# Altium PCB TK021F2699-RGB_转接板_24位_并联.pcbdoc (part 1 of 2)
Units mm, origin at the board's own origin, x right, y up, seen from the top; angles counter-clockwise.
Board outline 79.4 x 75.01 mm, 2 copper layers (Top Layer, Bottom Layer); 9 components, 37 nets, 108 pads, 115 vias.

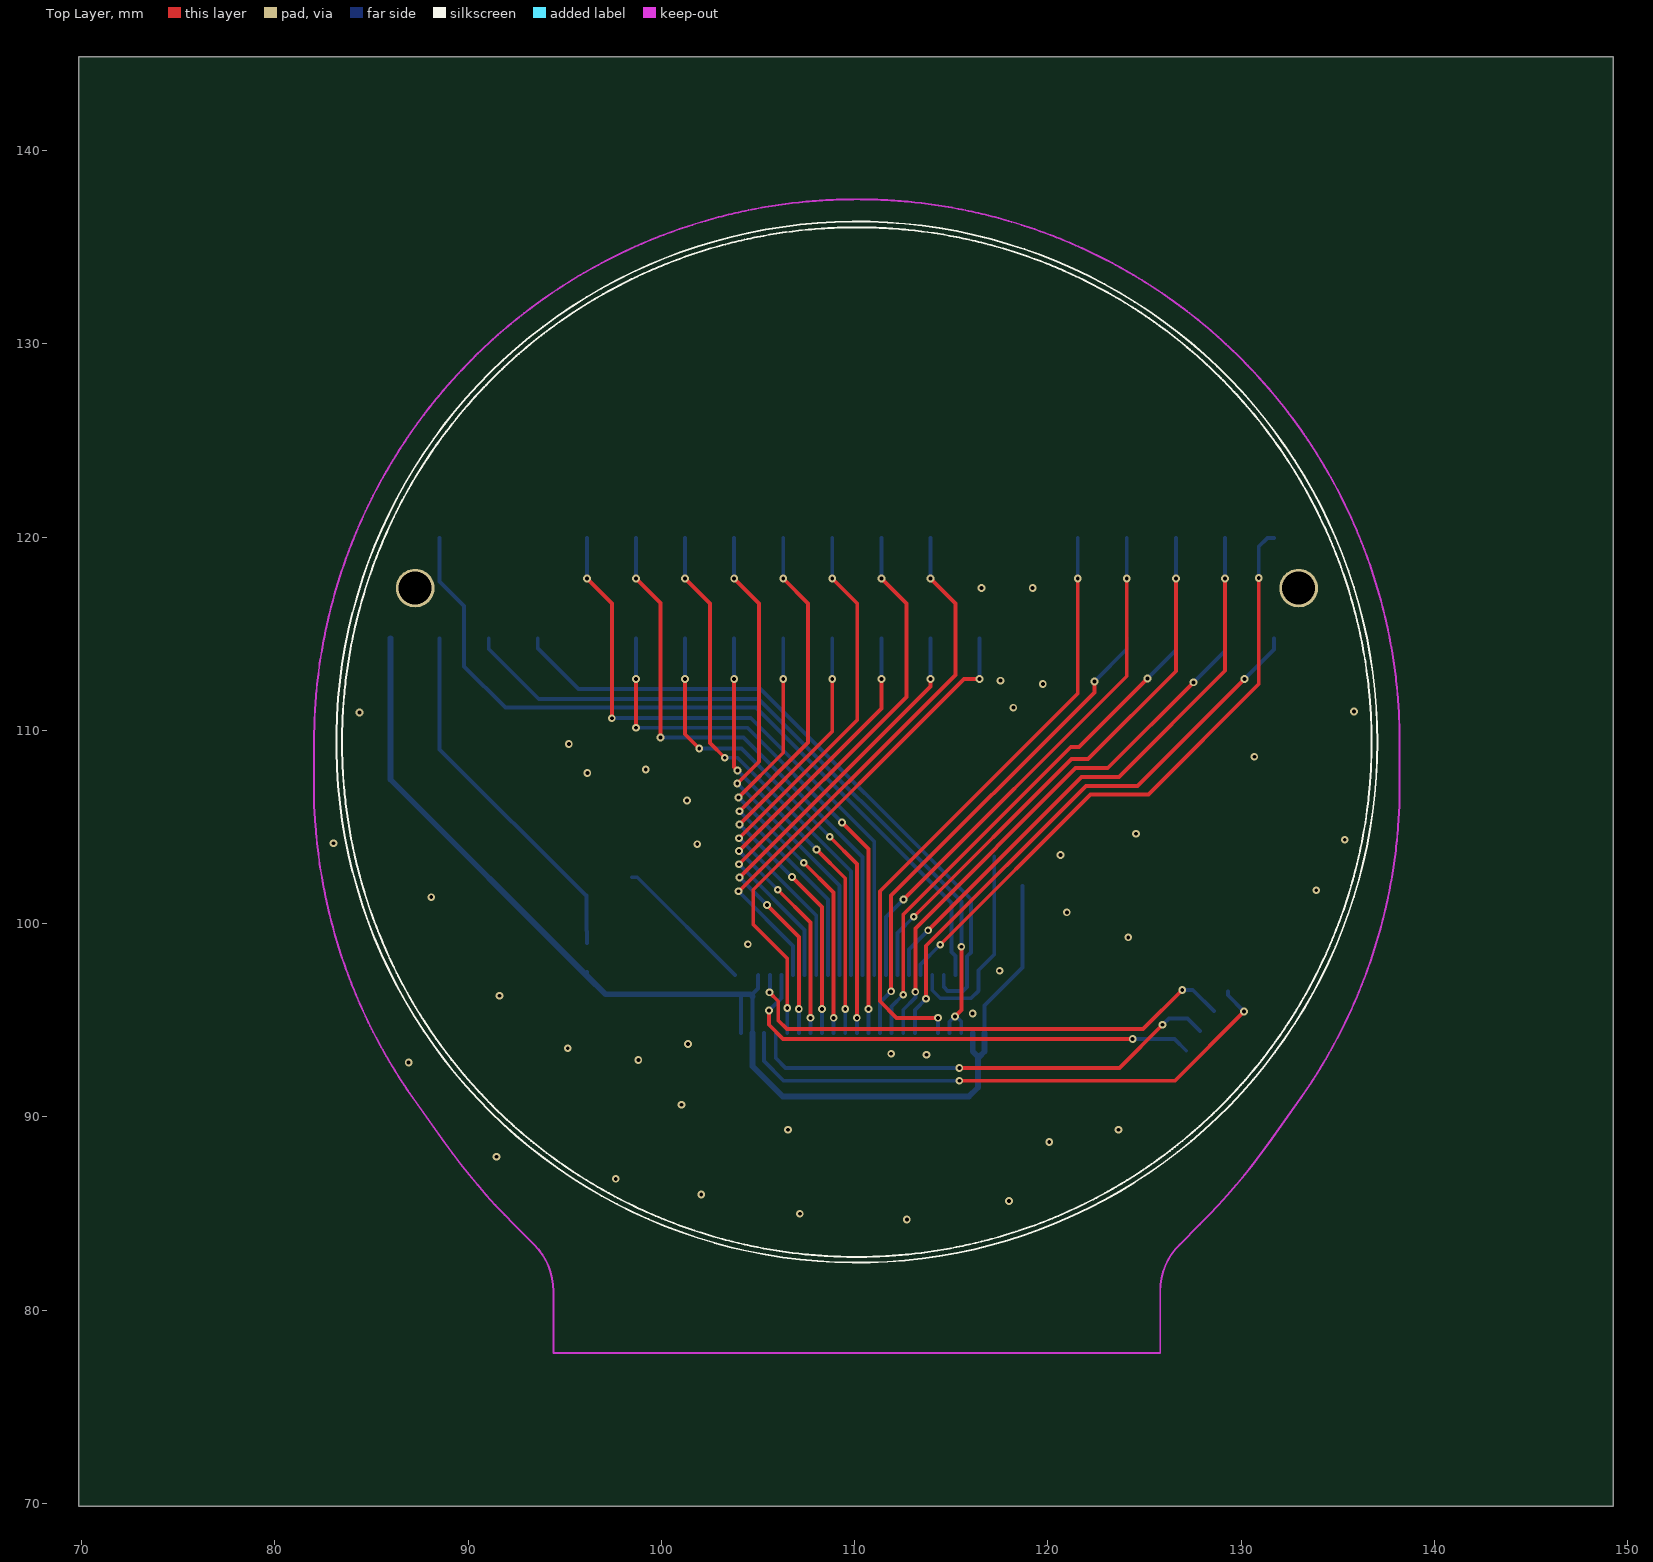
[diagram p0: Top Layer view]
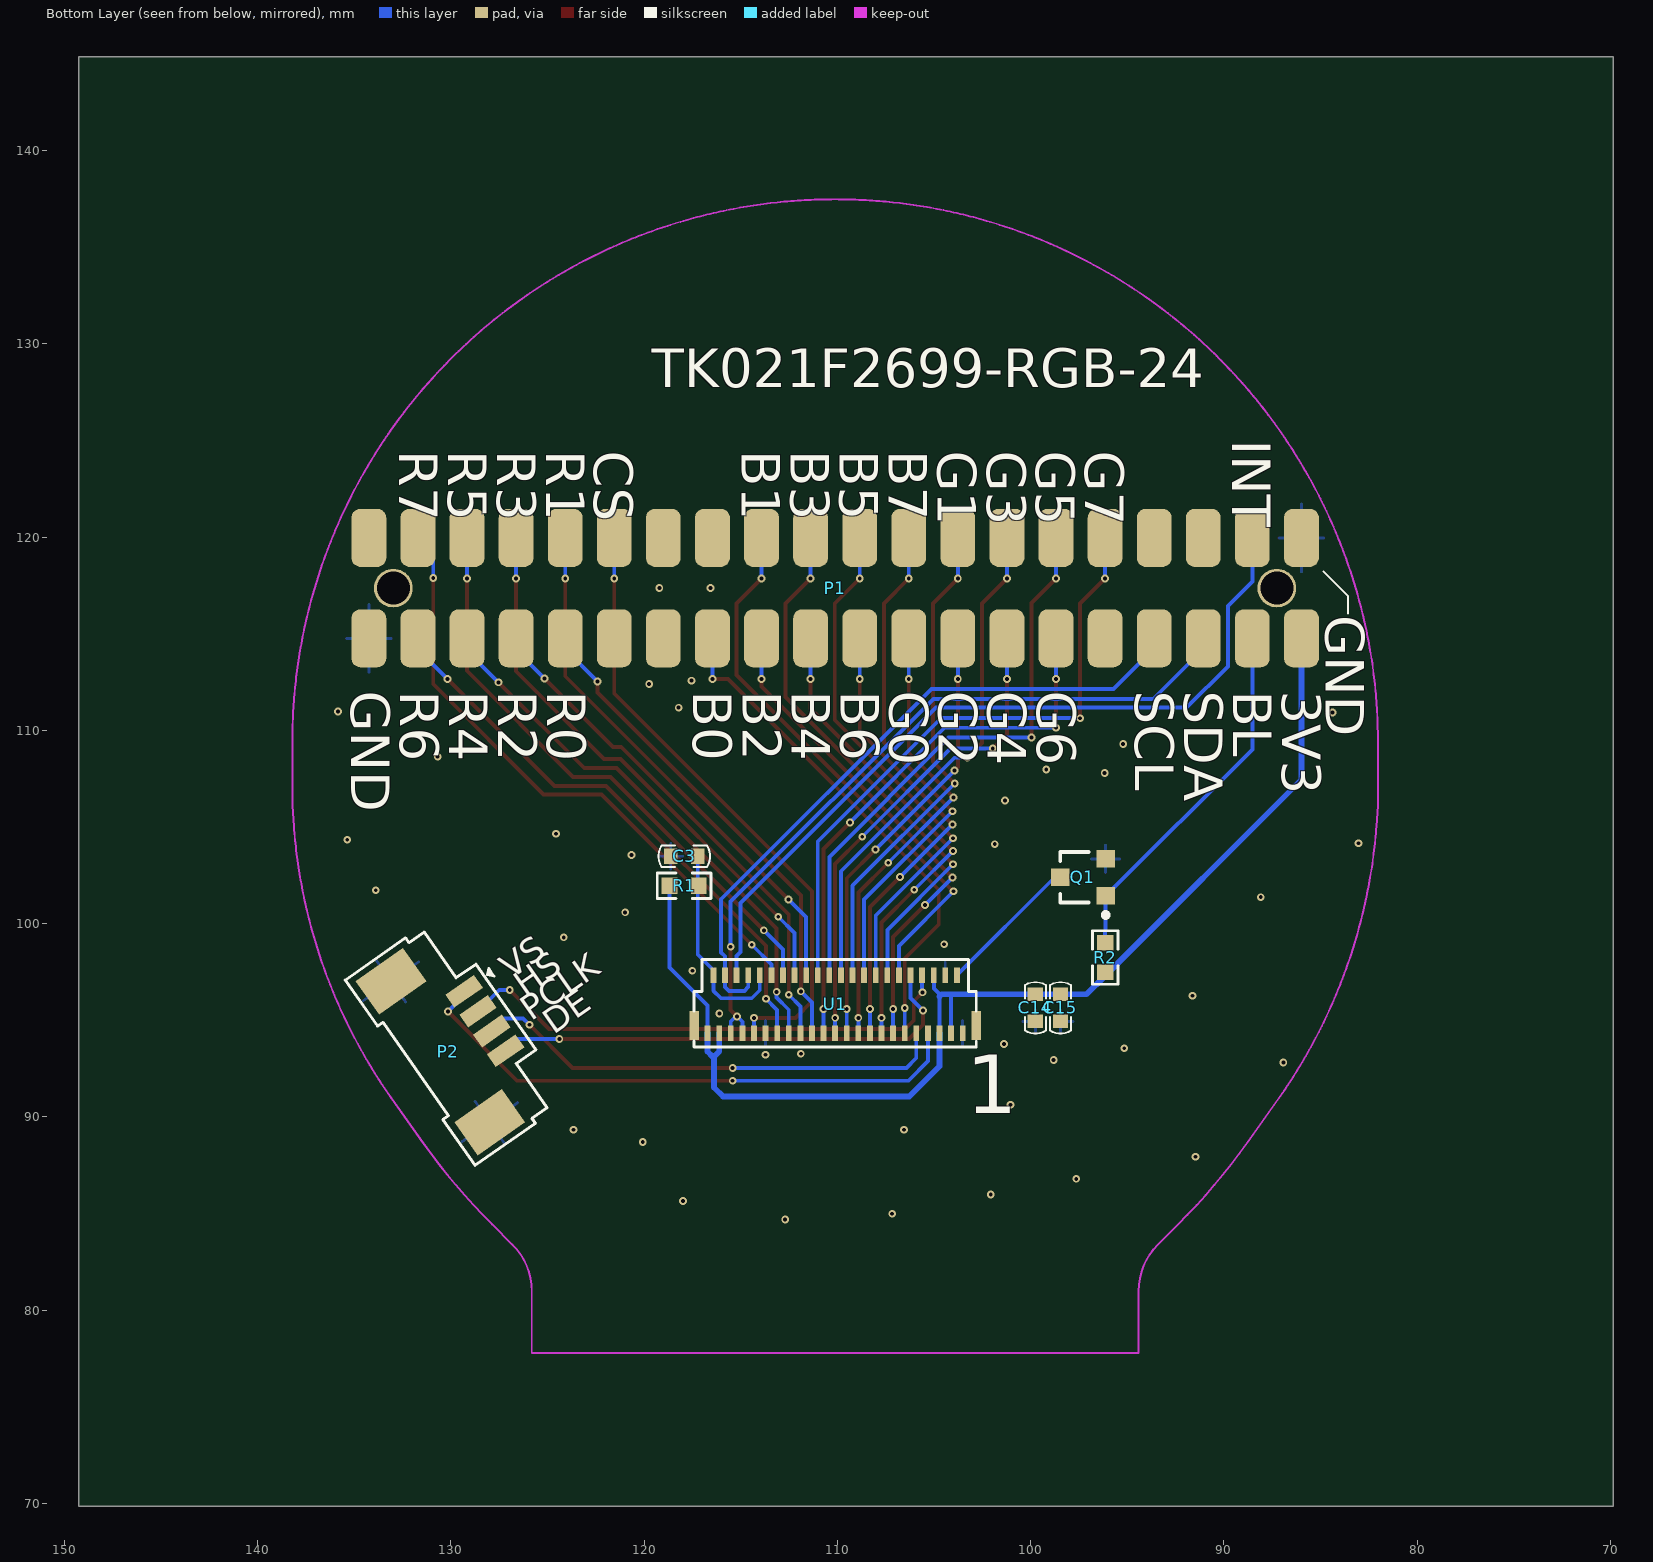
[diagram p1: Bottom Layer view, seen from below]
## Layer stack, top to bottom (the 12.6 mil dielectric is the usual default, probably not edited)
Top Layer: signal copper (thickness not stored)
Dielectric: dielectric 0.32, FR-4, Dk 4.8
Bottom Layer: signal copper (thickness not stored)

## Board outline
149.25,69.85 69.85,69.85 69.85,144.856 149.25,144.856

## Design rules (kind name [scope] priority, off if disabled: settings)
Clearance [All] p1: gap=0.178 ignorepadtopadclearanceinfootprint=FALSE except(0: Track-Poly SMDPad-Poly THPad-Poly Via-Poly Fill-Poly Region-Poly Poly-Poly Poly-Hole; 0.15: Track-Track Track-SMDPad SMDPad-SMDPad Track-THPad SMDPad-THPad THPad-THPad Track-Via SMDPad-Via THPad-Via Via-Via Track-Fill SMDPad-Fill THPad-Fill Via-Fill Fill-Fill Track-Region SMDPad-Region THPad-Region Via-Region Fill-Region Region-Region Track-Text SMDPad-Text THPad-Text Via-Text Fill-Text Region-Text Poly-Text Text-Text Track-Sheet SMDPad-Sheet THPad-Sheet Via-Sheet Fill-Sheet Region-Sheet Poly-Sheet Text-Sheet Track-Hole SMDPad-Hole THPad-Hole Via-Hole Fill-Hole Region-Hole Text-Hole Sheet-Hole)
Clearance Clearance_Polygon [All] p1: gap=0.178 ignorepadtopadclearanceinfootprint=FALSE except(0: Track-Text SMDPad-Text THPad-Text Via-Text Fill-Text Region-Text Poly-Text Text-Text Text-Hole; 0.15: Track-Track Track-SMDPad SMDPad-SMDPad Track-THPad SMDPad-THPad THPad-THPad Track-Via SMDPad-Via THPad-Via Via-Via Track-Fill SMDPad-Fill THPad-Fill Via-Fill Fill-Fill Track-Poly SMDPad-Poly THPad-Poly Via-Poly Fill-Poly Region-Poly Poly-Poly Track-Sheet SMDPad-Sheet THPad-Sheet Via-Sheet Fill-Sheet Region-Sheet Poly-Sheet Text-Sheet Track-Hole SMDPad-Hole THPad-Hole Via-Hole Fill-Hole Poly-Hole Sheet-Hole; 0.18: Track-Region SMDPad-Region THPad-Region Via-Region Fill-Region Region-Region Region-Hole)
DiffPairsRouting [All] p1: maxuncoupledlength=500 minlimit=5.9055 maxlimit=10 mostfreqgap=7.874 toplayer_minwidth=7.874 toplayer_prefwidth=7.874 toplayer_maxwidth=7.874 bottomlayer_minwidth=7.874 bottomlayer_prefwidth=7.874 bottomlayer_maxwidth=7.874
PasteMaskExpansion [All] p1:
PolygonConnect [All] p1: connectstyle=Relief reliefentries=4 reliefconductorwidth=5.9055 polygonreliefangle="90 Angle" airgapwidth=10
PolygonConnect PolygonConnect_1 [All] p1: connectstyle=Direct reliefentries=4 reliefconductorwidth=10 polygonreliefangle="90 Angle" airgapwidth=10
RoutingVias [All] p1: viastyle="Through Hole" holewidth=7.874 minholewidth=7.874 maxholewidth=27.9922 width=15.748 minwidth=15.748 maxwidth=50
SolderMaskExpansion [All] p1: useseparateexpansions=TRUE expansion=3.937 expansionbottom=3.937
Width [All] p1: maxlimit=16 minlimit=8 preferedwidth=8
1 further rules are at their usual default settings.

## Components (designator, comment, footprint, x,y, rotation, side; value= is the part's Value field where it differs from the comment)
C3 "CC0603KRX7R9BB104" C0603 117.932,103.48 r0 bottom
C14 "104" C0603-1 99.746,96.345 r270 bottom
C15 "475" C0603-2 98.45,96.345 r270 bottom
P1 "PIN_Header_40PIN" P_Head_2x20 134.242,119.964 r180 bottom locked
P2 "BHEADSMD1x4" BHEADSMD1x4 129.311,96.495 r55 bottom
Q1 "SI2302" SOT23A 96.114,101.448 r90 bottom
R1 "0603WAF1802T5E" R0603 117.932,101.956 r0 bottom
R2 "0603WAF1802T5E" R0603 96.139,98.247 r270 bottom
U1 "TK-RGB-45P" tk043f-45p 103.512,94.336 r0 bottom locked

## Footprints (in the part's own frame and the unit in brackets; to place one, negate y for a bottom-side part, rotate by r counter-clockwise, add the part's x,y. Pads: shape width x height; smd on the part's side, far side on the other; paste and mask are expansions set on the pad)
BHEADSMD1x4 [mil]
  rect 32x71 smd: 1(0,0) 2(-49.21,0) 3(-98.43,0) 4(-147.64,0)
  rect 83x118 smd: 5(102.36,110.24) 6(-248.03,110.24)
  silkscreen extent -303,-68 158,185
C0603 [mm]
  rect 0.7x0.8 smd: 1(-0.712,-0.007) 2(0.688,-0.007)
  silkscreen extent -1.33,-0.56 1.31,0.54
C0603-1 [mm]
  rect 0.7x0.8 smd: 1(0,0) 2(1.4,0)
  silkscreen extent -0.62,-0.55 2.02,0.55
C0603-2 [mm]
  rect 0.7x0.8 smd: 1(0,0) 2(1.4,0)
  silkscreen extent -0.62,-0.55 2.02,0.55
P_Head_2x20 [mm]
  round 2 hole 1.7: 0(1.27,-2.6) 0(46.99,-2.6)
  rrect50% 1.8x3 smd: 1(0,0) 2(0,-5.2) 3(2.54,0) 4(2.54,-5.2) 5(5.08,0) 6(5.08,-5.2) 7(7.62,0) 8(7.62,-5.2) 9(10.16,0) 10(10.16,-5.2) 11(12.7,0) 12(12.7,-5.2) 13(15.24,0) 14(15.24,-5.2) 15(17.78,0) 16(17.78,-5.2) 17(20.32,0) 18(20.32,-5.2) 19(22.86,0) 20(22.86,-5.2) 21(25.4,0) 22(25.4,-5.2) 23(27.94,0) 24(27.94,-5.2) 25(30.48,0) 26(30.48,-5.2) 27(33.02,0) 28(33.02,-5.2) 29(35.56,0) 30(35.56,-5.2) 31(38.1,0) 32(38.1,-5.2) 33(40.64,0) 34(40.64,-5.2) 35(43.18,0) 36(43.18,-5.2) 37(45.72,0) 38(45.72,-5.2) 39(48.26,0) 40(48.26,-5.2)
R0603 [mm]
  rect 0.806x0.864 smd: 1(-0.753,0) 2(0.753,0)
  silkscreen extent -1.39,-0.66 1.39,0.66
SOT23A [mm]
  rect 0.9x0.95 smd: 1(0,0) 2(1.9,0) 3(0.95,2.35)
  silkscreen extent -1.12,-0.12 2.25,2.35
tk043f-45p [mm]
  rect 0.5x1.5 smd: 0(-0.7,-0.4) 0(13.9,-0.4)
  rect 0.3x0.8 smd: 1(0,0) 2(0.3,-3) 3(0.6,0) 4(0.9,-3) 5(1.2,0) 6(1.5,-3) 7(1.8,0) 8(2.1,-3) 9(2.4,0) 10(2.7,-3) 11(3,0) 12(3.3,-3) 13(3.6,0) 14(3.9,-3) 15(4.2,0) 16(4.5,-3) 17(4.8,0) 18(5.1,-3) 19(5.4,0) 20(5.7,-3) 21(6,0) 22(6.3,-3) 23(6.6,0) 24(6.9,-3) 25(7.2,0) 26(7.5,-3) 27(7.8,0) 28(8.1,-3) 29(8.4,0) 30(8.7,-3) 31(9,0) 32(9.3,-3) 33(9.6,0) 34(9.9,-3) 35(10.2,0) 36(10.5,-3) 37(10.8,0) 38(11.1,-3) 39(11.4,0) 40(11.7,-3) 41(12,0) 42(12.3,-3) 43(12.6,0) 44(12.9,-3) 45(13.2,0)
  silkscreen extent -0.7,-3.8 13.9,0.73

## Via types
v1: diameter 0.4, hole 0.2, Top Layer to Bottom Layer, 115 vias

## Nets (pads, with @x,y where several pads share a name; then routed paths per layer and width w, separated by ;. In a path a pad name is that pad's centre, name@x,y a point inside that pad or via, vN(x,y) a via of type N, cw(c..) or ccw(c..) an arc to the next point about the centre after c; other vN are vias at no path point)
3.3V: C14.1 C15.1 P1.40 R1.2 R2.2 U1.3 U1.5 U1.6 U1.43 U1.45 | length 62.9
  Bottom Layer w0.2: R2.2@96.139,97.307 R2.2@96.139,97.494 ; U1.3@104.112,94.336 104.112,96.33 104.127,96.345 ; U1.5@104.712,94.336 104.712,96.228 104.712,96.355 105.004,96.647 105.004,97.328 U1.6@105.012,97.336 ; U1.45@116.712,94.336 116.712,95.757 118.686,97.731 R1.2@118.686,101.956
  Bottom Layer w0.3: P1.40@85.982,114.764 85.982,107.465 96.139,97.307 97.101,96.345 C15.1@98.45,96.345 C14.1@99.746,96.345 104.127,96.345 104.595,96.345 104.712,96.228 ; U1.5@104.712,94.336 104.712,92.617 106.279,91.05 115.909,91.05 116.383,91.524 116.383,93.116 116.112,93.387 U1.43@116.112,94.336 ; 116.441,93.116 116.712,93.387 U1.45@116.712,94.336
B0: P1.16 U1.11 | length 26.5
  Top Layer w0.2: v1(106.512,95.631) 106.512,98.187 104.75,99.949 104.75,101.752 115.66,112.663 v1(116.462,112.663)
  Bottom Layer w0.2: U1.11@106.512,94.336 v1(106.512,95.631) ; v1(116.462,112.663) P1.16@116.462,114.764
B1: P1.17 U1.12 | length 29
  Top Layer w0.2: v1(103.988,101.676) 104.02,101.676 115.212,112.868 115.212,116.573 v1(113.922,117.863)
  Bottom Layer w0.2: v1(103.988,101.676) 106.812,98.852 U1.12@106.812,97.336 ; v1(113.922,117.863) P1.17@113.922,119.964
B2: P1.18 U1.13 | length 25.8
  Top Layer w0.2: v1(104.038,102.387) 113.922,112.271 v1(113.922,112.663) ; v1(105.461,100.965) 107.112,99.314 v1(107.112,95.581)
  Bottom Layer w0.2: v1(104.038,102.387) v1(105.461,100.965) ; U1.13@107.112,94.336 v1(107.112,95.581) ; v1(113.922,112.663) P1.18@113.922,114.764
B3: P1.19 U1.14 | length 28.2
  Top Layer w0.2: v1(104.013,103.073) 112.672,111.732 112.672,116.573 v1(111.382,117.863)
  Bottom Layer w0.2: v1(104.013,103.073) 107.412,99.674 U1.14@107.412,97.336 ; v1(111.382,117.863) P1.19@111.382,119.964
B4: P1.20 U1.15 | length 25
  Top Layer w0.2: v1(104.014,103.759) 111.382,111.126 v1(111.382,112.663) ; v1(106.02,101.753) 107.712,100.062 v1(107.712,95.123)
  Bottom Layer w0.2: v1(104.014,103.759) v1(106.02,101.753) ; U1.15@107.712,94.336 v1(107.712,95.123) ; v1(111.382,112.663) P1.20@111.382,114.764
B5: P1.21 U1.16 | length 27.4
  Top Layer w0.2: v1(104.013,104.419) 110.132,110.538 110.132,116.573 v1(108.842,117.863)
  Bottom Layer w0.2: v1(104.013,104.419) 108.012,100.421 U1.16@108.012,97.336 ; v1(108.842,117.863) P1.21@108.842,119.964
B6: P1.22 U1.17 | length 24.2
  Top Layer w0.2: v1(104.038,105.131) 108.842,109.934 v1(108.842,112.663) ; v1(106.756,102.413) 108.312,100.857 v1(108.312,95.581)
  Bottom Layer w0.2: v1(104.038,105.131) v1(106.756,102.413) ; U1.17@108.312,94.336 v1(108.312,95.581) ; v1(108.842,112.663) P1.22@108.842,114.764
B7: P1.23 U1.18 | length 26.5
  Top Layer w0.2: v1(104.038,105.816) 107.592,109.37 107.592,116.573 v1(106.302,117.863)
  Bottom Layer w0.2: v1(104.038,105.816) 108.612,101.243 U1.18@108.612,97.336 ; v1(106.302,117.863) P1.23@106.302,119.964
BL_CTR: P1.38 Q1.1 R2.1 | length 18.9
  Bottom Layer w0.2: P1.38@88.522,114.764 88.522,109.014 96.089,101.448 Q1.1@96.114,101.448 96.114,99.629 96.139,99.604 R2.1@96.139,99.001
CS: P1.11 U1.37 | length 32.4
  Top Layer w0.2: v1(114.312,95.123) 112.166,95.123 111.303,95.987 111.303,101.676 121.542,111.915 v1(121.542,117.863)
  Bottom Layer w0.2: U1.37@114.312,94.336 v1(114.312,95.123) ; v1(121.542,117.863) P1.11@121.542,119.964
G0: P1.24 U1.19 | length 23.4
  Top Layer w0.2: v1(103.988,106.528) 106.302,108.842 v1(106.302,112.663) ; v1(107.366,103.149) 108.912,101.603 v1(108.912,95.123)
  Bottom Layer w0.2: v1(103.988,106.528) v1(107.366,103.149) ; v1(106.302,112.663) P1.24@106.302,114.764 ; U1.19@108.912,94.336 v1(108.912,95.123)
G1: P1.25 U1.20 | length 25.8
  Top Layer w0.2: v1(103.762,117.863) 105.052,116.573 105.052,108.379 v1(103.924,107.251)
  Bottom Layer w0.2: v1(103.762,117.863) P1.25@103.762,119.964 ; v1(103.924,107.251) 109.212,101.964 U1.20@109.212,97.336
G2: P1.26 U1.21 | length 22.8
  Top Layer w0.2: v1(103.762,112.663) 103.762,108.1 v1(103.937,107.925) ; v1(108.026,103.835) 109.512,102.35 v1(109.512,95.581)
  Bottom Layer w0.2: v1(103.762,112.663) P1.26@103.762,114.764 ; v1(103.937,107.925) v1(108.026,103.835) ; U1.21@109.512,94.336 v1(109.512,95.581)
G3: P1.27 U1.22 | length 26.6
  Top Layer w0.2: v1(101.222,117.863) 102.512,116.573 102.512,109.35 v1(103.276,108.585)
  Bottom Layer w0.2: v1(101.222,117.863) P1.27@101.222,119.964 ; v1(103.276,108.585) 103.937,108.585 109.812,102.71 U1.22@109.812,97.336
G4: P1.28 U1.23 | length 25.4
  Top Layer w0.2: v1(101.222,112.663) 101.222,109.801 v1(101.956,109.068) ; v1(108.712,104.496) 110.112,103.096 v1(110.112,95.123)
  Bottom Layer w0.2: v1(101.222,112.663) P1.28@101.222,114.764 ; v1(101.956,109.068) 104.14,109.068 v1(108.712,104.496) ; U1.23@110.112,94.336 v1(110.112,95.123)
G5: P1.29 U1.24 | length 30
  Top Layer w0.2: v1(98.682,117.863) 99.949,116.596 v1(99.949,109.633)
  Bottom Layer w0.2: v1(98.682,117.863) P1.29@98.682,119.964 ; v1@99.949,109.626 104.242,109.626 110.412,103.456 U1.24@110.412,97.336
G6: P1.30 U1.25 | length 28.8
  Top Layer w0.2: v1(98.679,110.134) 98.682,110.137 v1(98.682,112.663) ; v1(109.347,105.232) 110.712,103.867 v1(110.712,95.581)
  Bottom Layer w0.2: v1(98.679,110.134) 104.445,110.134 v1(109.347,105.232) ; v1(98.682,112.663) P1.30@98.682,114.764 ; U1.25@110.712,94.336 v1(110.712,95.581)
G7: P1.31 U1.26 | length 33
  Top Layer w0.2: v1(96.142,117.863) 97.432,116.573 v1(97.432,110.629)
  Bottom Layer w0.2: v1(96.142,117.863) P1.31@96.142,119.964 ; v1@97.434,110.642 104.623,110.642 111.012,104.253 U1.26@111.012,97.336
GND: C3.2 C14.2 C15.2 P1.2 P1.39 P2.5 P2.6 Q1.2 U1.1 U1.4 U1.35
  other v1: 112.7,84.684 107.163,84.988 117.983,85.649 102.057,85.979 97.638,86.792 91.465,87.935 120.066,88.697 106.553,89.332 123.647,89.332 101.041,90.627 86.919,92.812 98.806,92.939 113.716,93.218 111.887,93.269 95.148,93.548 101.371,93.777 116.103,95.352 91.618,96.266 117.5,97.561 104.47,98.933 124.155,99.289 120.98,100.584 88.087,101.371 133.883,101.727 120.65,103.556 101.854,104.115 83.033,104.159 135.357,104.343 124.562,104.648 101.321,106.375 96.164,107.798 99.187,107.975 130.683,108.636 95.208,109.297 84.379,110.922 135.839,110.973 118.212,111.176 119.736,112.395 117.551,112.573 116.563,117.364 119.209,117.364
INT: P1.37 U1.40 | length 41.3
  Bottom Layer w0.2: P1.37@88.522,119.964 88.522,117.701 89.789,116.434 89.789,113.309 91.923,111.176 104.902,111.176 115.012,101.066 115.012,98.526 115.212,98.326 U1.40@115.212,97.336
LED-: Q1.3 U1.2 | length 7.4
  Bottom Layer w0.2: Q1.3@98.464,102.398 98.75,102.398 U1.2@103.812,97.336
R0: P1.10 U1.27 | length 25.7
  Top Layer w0.2: v1(111.887,96.495) 111.887,101.448 122.405,111.966 v1(122.405,112.536)
  Bottom Layer w0.2: U1.27@111.312,94.336 111.312,95.919 v1(111.887,96.495) ; v1(122.405,112.536) 124.082,114.212 P1.10@124.082,114.764
R1: 
R2: P1.8 U1.29 | length 26.8
  Top Layer w0.2: v1(112.512,96.317) 112.512,100.472 121.181,109.14 121.6,109.14 v1(125.149,112.688)
  Bottom Layer w0.2: U1.29@111.912,94.336 111.912,95.716 v1(112.512,96.317) ; v1(125.149,112.688) 126.622,114.162 P1.8@126.622,114.764
R3: P1.7 U1.30 | length 29.1
  Top Layer w0.2: v1(113.055,100.355) 121.211,108.511 122.075,108.511 126.622,113.058 v1(126.622,117.863)
  Bottom Layer w0.2: U1.30@112.212,97.336 112.212,99.512 v1(113.055,100.355) ; v1(126.622,117.863) P1.7@126.622,119.964
R4: P1.6 U1.31 | length 28.3
  Top Layer w0.2: v1(113.138,96.469) 113.138,99.752 113.266,99.881 121.432,108.046 123.097,108.046 v1(127.536,112.485)
  Bottom Layer w0.2: U1.31@112.512,94.336 112.512,95.545 113.138,96.171 v1(113.138,96.469) ; v1(127.536,112.485) 129.162,114.111 P1.6@129.162,114.764
R5: P1.5 U1.32 | length 30.5
  Top Layer w0.2: v1(113.8,99.652) 121.744,107.596 123.674,107.596 129.162,113.084 v1(129.162,117.863)
  Bottom Layer w0.2: U1.32@112.812,97.336 112.812,98.664 v1(113.8,99.652) ; v1(129.162,117.863) P1.5@129.162,119.964
R6: P1.4 U1.33 | length 29.7
  Top Layer w0.2: v1(113.687,96.114) 113.687,98.853 121.964,107.13 124.645,107.13 v1(130.178,112.663)
  Bottom Layer w0.2: U1.33@113.112,94.336 113.112,95.538 v1(113.687,96.114) ; v1(130.178,112.663) 131.702,114.187 P1.4@131.702,114.764
R7: P1.3 U1.34 | length 32.2
  Top Layer w0.2: v1(114.427,98.908) 122.199,106.68 125.197,106.68 130.912,112.395 v1(130.912,117.881)
  Bottom Layer w0.2: U1.34@113.412,97.336 113.412,97.892 v1(114.427,98.908) ; v1(130.912,117.881) 130.912,119.507 131.369,119.964 P1.3@131.702,119.964
RST: C3.1 R1.1 U1.36 U1.44 | length 10.8
  Bottom Layer w0.2: U1.36@114.012,97.336 114.012,96.554 114.427,96.139 116.027,96.139 116.412,96.524 U1.44@116.412,97.336 116.412,97.586 117.22,98.394 C3.1@117.22,103.487
SCL: P1.34 U1.38 U1.42 | length 34.9
  Bottom Layer w0.2: P1.34@93.602,114.764 93.602,114.246 95.707,112.141 105.131,112.141 116.012,101.26 116.012,98.511 115.812,98.311 U1.42@115.812,97.336 115.812,96.72 115.612,96.52 114.812,96.52 114.612,96.72 U1.38@114.612,97.336
SDA: P1.36 U1.39 U1.41 | length 38.5
  Top Layer w0.2: v1(115.191,95.199) 115.519,95.527 v1(115.519,98.806)
  Bottom Layer w0.2: P1.36@91.062,114.764 91.062,114.221 93.65,111.633 105.029,111.633 115.519,101.143 v1(115.519,98.806) ; U1.39@114.912,94.336 114.912,94.92 v1(115.191,95.199) 115.24,95.199 115.512,94.927 U1.41@115.512,94.336
T_DE: P2.4 U1.10 | length 25
  Top Layer w0.2: v1(105.562,95.504) 105.562,94.767 106.299,94.031 v1(124.384,94.031)
  Bottom Layer w0.2: v1(105.562,95.504) 106.212,96.153 U1.10@106.212,97.336 ; v1(124.384,94.031) 126.552,94.031 P2.4@127.16,93.423
T_HSYNC: P2.2 U1.8 | length 26.6
  Top Layer w0.2: v1(105.588,96.444) 106.045,95.987 106.045,94.996 106.502,94.539 124.917,94.539 v1(126.949,96.571)
  Bottom Layer w0.2: v1(105.588,96.444) 105.612,96.468 U1.8@105.612,97.336 ; v1(126.949,96.571) 127.494,96.571 P2.2@128.594,95.471
T_PCLK: P2.3 U1.9 | length 24.8
  Top Layer w0.2: v1(115.418,92.532) 123.698,92.532 v1(125.933,94.767)
  Bottom Layer w0.2: U1.9@105.912,94.336 105.912,93.046 106.426,92.532 v1(115.418,92.532) ; v1(125.933,94.767) 126.263,95.098 127.227,95.098 P2.3@127.877,94.447
T_VSYNC: P2.1 U1.7 | length 29.6
  Top Layer w0.2: v1(115.418,91.872) 126.568,91.872 v1(130.15,95.453)
  Bottom Layer w0.2: U1.7@105.312,94.336 105.312,92.884 106.324,91.872 v1(115.418,91.872) ; P2.1@129.311,96.495 129.311,96.291 v1(130.15,95.453)
pads on no net: P1.0 P1.1 P1.9 P1.12 P1.13 P1.14 P1.15 P1.32 P1.33 P1.35 U1.0 U1.28
copper on no net: | length 27.8
  Top Layer w0.2: v1(112.522,101.244) 124.082,112.804 v1(124.082,117.863)
  Bottom Layer w0.2: 111.612,97.336 111.612,100.334 v1(112.522,101.244) ; v1(124.082,117.863) 124.082,119.964

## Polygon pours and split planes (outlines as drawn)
GND on Top Layer (solid, remove dead copper): 81.686,76.2 138.76,76.2 138.76,138.227 81.686,138.227
GND on Bottom Layer (solid, remove dead copper, pour order 2): 76.2,76.479 142.9,76.479 142.9,138.506 76.2,138.506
